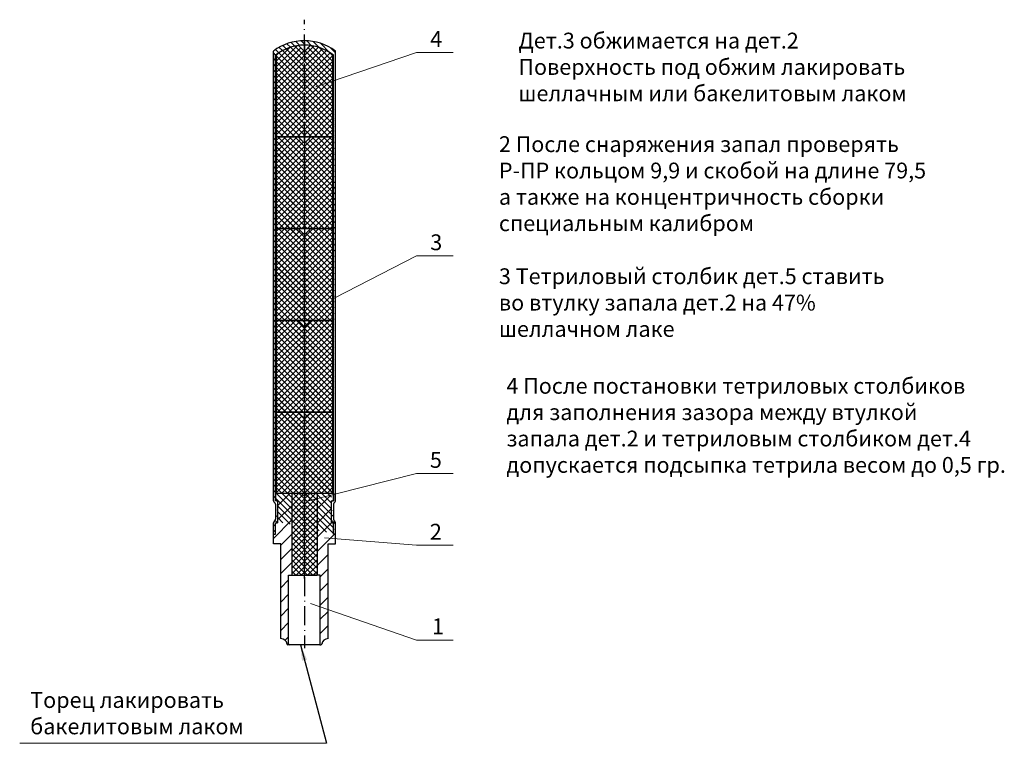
# Model space of a CAD drawing. Units: millimetres. Extents: x -45 to 111, y -40 to 75.
import ezdxf

# ---------------------------------------------------------------- set-up
doc = ezdxf.new("R2010")
doc.units = ezdxf.units.MM
doc.linetypes.add('ACAD_ISO10W100', pattern=[18, 12, -3, 0, -3])
doc.dimstyles.new('ISO-25', dxfattribs={"dimtxt": 2.5, "dimasz": 2.5, "dimexe": 1.25, "dimexo": 0.625, "dimtad": 1, "dimtxsty": 'Standard', "dimcen": 2.5, "dimadec": 0, "dimazin": 0, "dimtfac": 1, "dimtmove": 0, "dimatfit": 3, "dimfxl": 0, "dimarcsym": 0})
pattern_1 = [(45, (0, 0), (-0.4490128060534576, 0.4490128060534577), []), (135, (0, 0), (-0.4490128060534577, -0.4490128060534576), [])]
pattern_2 = [(135, (0, 0), (-0.4490128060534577, -0.4490128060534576), []), (225, (0, 0), (0.4490128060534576, -0.4490128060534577), [])]
pattern_3 = [(45, (0, 0), (-1.122532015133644, 1.122532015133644), [])]

# ---------------------------------------------------------------- blocks, each defined once
blk = doc.blocks.new('tetril_stolbik_8_92')
at = {"lineweight": 15, "ltscale": 0.25}
h = blk.add_hatch(dxfattribs=at)
h.set_pattern_fill('ANSI37', scale=0.2, angle=90, style=0)
h.set_pattern_definition(pattern_2)
h.paths.add_polyline_path([(4.469813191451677e-15, 14.5), (-4.46, 14.5), (-4.46, 5.461744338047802e-16), (-1, 5.461744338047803e-16), (3.367667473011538e-16, 1)])
h.paths.add_polyline_path([(4.460000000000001, 14.5), (4.469813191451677e-15, 14.5), (3.367667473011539e-16, 1), (1, 5.461744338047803e-16), (4.46, 5.461744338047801e-16)])
at = {"color": 1, "linetype": 'ACAD_ISO10W100', "lineweight": 25, "ltscale": 0.25}
blk.add_line((-1.224606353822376e-16, -0.4999999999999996), (7.53132907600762e-15, 24.5), dxfattribs=at)
at = {"color": 7, "lineweight": 30, "ltscale": 0.25}
for p, q in [((-4.46, 5.461744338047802e-16), (-4.459999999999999, 14.5)), ((4.460000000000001, 14.5), (-4.459999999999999, 14.5)), ((4.46, 5.461744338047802e-16), (4.460000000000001, 14.5)), ((-4.46, 5.461744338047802e-16), (4.46, 5.461744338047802e-16)), ((-1, 5.461744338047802e-16), (3.367667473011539e-16, 1)), ((3.367667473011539e-16, 1), (1, 5.461744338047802e-16))]:
    blk.add_line(p, q, dxfattribs=at)
blk = doc.blocks.new('tetril_stolbik_4')
at = {"lineweight": 15, "ltscale": 0.25}
h = blk.add_hatch(dxfattribs=at)
h.set_pattern_fill('ANSI37', scale=0.2, angle=90, style=0)
h.set_pattern_definition(pattern_2)
h.paths.add_polyline_path([(3.857510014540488e-15, 12.5), (-0.4999999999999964, 13), (-1.999999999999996, 13), (-2, 2.449212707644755e-16), (-0.4999999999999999, 2.449212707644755e-16), (1.836909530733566e-16, 0.5000000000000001)])
h.paths.add_polyline_path([(2.000000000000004, 13), (0.5000000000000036, 13), (3.857510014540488e-15, 12.5), (1.836909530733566e-16, 0.5000000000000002), (0.5, 2.449212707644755e-16), (2.000000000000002, 2.449212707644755e-16)])
at = {"color": 1, "linetype": 'ACAD_ISO10W100', "lineweight": 25, "ltscale": 0.25}
blk.add_line((-1.224606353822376e-16, -0.4999999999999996), (7.53132907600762e-15, 24.5), dxfattribs=at)
at = {"color": 7, "lineweight": 30, "ltscale": 0.25}
for p, q in [((-1.999999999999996, 13), (-2, 2.449212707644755e-16)), ((-1.999999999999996, 13), (2.000000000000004, 13)), ((-0.499999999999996, 13), (3.918740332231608e-15, 12.5)), ((3.918740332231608e-15, 12.5), (0.500000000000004, 13)), ((2.000000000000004, 13), (2.000000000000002, 2.449212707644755e-16)), ((-2, 2.449212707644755e-16), (2, 2.449212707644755e-16)), ((1.836909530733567e-16, 0.5000000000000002), (-0.4999999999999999, 2.449212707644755e-16)), ((0.5, 2.449212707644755e-16), (1.836909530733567e-16, 0.5000000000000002))]:
    blk.add_line(p, q, dxfattribs=at)

msp = doc.modelspace()

# ---------------------------------------------------------------- hatches: boundary and pattern name
at = {"linetype": 'ByBlock', "lineweight": 15}
h = msp.add_hatch(dxfattribs=at)
h.set_pattern_fill('ANSI31', scale=0.2, angle=90, style=0)
h.set_pattern_definition([(135, (0, 0), (-0.4490128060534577, -0.4490128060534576), [])])
edge = h.paths.add_edge_path()
edge.add_line((-4.910000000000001, -6.499999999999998), (-4.574999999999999, -6.499999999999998))
edge.add_line((-4.574999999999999, -6.499999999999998), (-4.574999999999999, -4.699999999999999))
edge.add_line((-4.910000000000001, -6.499999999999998), (-4.910000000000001, -4.699999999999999))
edge.add_line((-4.574999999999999, -4.699999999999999), (-4.250000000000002, -4.699999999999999))
edge.add_arc((-4.450000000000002, -4.499999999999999), 0.2000000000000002, 270, 360)
edge.add_arc((-4.574999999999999, -4.699999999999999), 0.3350000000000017, 119.7398696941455, 180)
edge.add_arc((-4.890000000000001, -4.148638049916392), 0.3, 299.7398696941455, 360)
edge.add_line((-4.25, -1.200000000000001), (-4.250000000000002, -4.699999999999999))
edge.add_line((-4.59, -1.751361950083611), (-4.590000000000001, -4.148638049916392))
edge.add_arc((-4.45, -1.4), 0.2000000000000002, 359.9999999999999, 449.9999999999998)
edge.add_line((-4.25, -1.200000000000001), (-4.575, -1.2))
edge.add_line((-4.574999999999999, -1.2), (-4.574999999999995, 69.24301060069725))
edge.add_arc((-4.89, -1.751361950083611), 0.3, 0, 60.26013030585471)
edge.add_arc((-4.574999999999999, -1.2), 0.3350000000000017, 180, 240.2601303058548)
edge.add_line((-4.910000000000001, -1.2), (-4.909999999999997, 69.8674881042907))
edge.add_arc((3.385697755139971e-15, 63.29999999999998), 8.200000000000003, 53.21739364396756, 126.7826063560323)
edge.add_arc((3.385697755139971e-15, 63.29999999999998), 7.5, 52.41049703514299, 127.5895029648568)
edge.add_line((4.574999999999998, -1.200000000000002), (4.575000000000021, 69.24301060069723))
edge.add_line((4.91, -1.200000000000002), (4.910000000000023, 69.86748810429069))
edge.add_line((4.25, -1.200000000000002), (4.575, -1.200000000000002))
edge.add_arc((4.450000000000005, -1.400000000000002), 0.2000000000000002, 90.00000000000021, 180)
edge.add_arc((4.575000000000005, -1.200000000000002), 0.3350000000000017, 299.7398696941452, 360)
edge.add_arc((4.890000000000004, -1.751361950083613), 0.3, 119.7398696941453, 180)
edge.add_line((4.25, -1.200000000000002), (4.249999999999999, -4.700000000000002))
edge.add_line((4.590000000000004, -1.751361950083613), (4.590000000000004, -4.148638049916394))
edge.add_arc((4.450000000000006, -4.500000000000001), 0.2000000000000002, 180, 270)
edge.add_line((4.574999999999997, -4.700000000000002), (4.249999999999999, -4.700000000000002))
edge.add_arc((4.890000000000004, -4.148638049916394), 0.3, 180, 240.2601303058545)
edge.add_arc((4.575000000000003, -4.700000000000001), 0.3350000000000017, 0, 60.26013030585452)
edge.add_line((4.574999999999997, -6.5), (4.574999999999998, -4.700000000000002))
edge.add_line((4.909999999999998, -6.5), (4.909999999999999, -4.696309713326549))
edge.add_line((4.574999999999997, -6.500000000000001), (4.909999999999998, -6.5))
h = msp.add_hatch(dxfattribs=at)
h.set_pattern_fill('ANSI37', scale=0.2, style=0)
h.set_pattern_definition(pattern_1)
h.paths.add_polyline_path([(3.093486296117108e-15, 69.79999999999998), (-0.9407636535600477, 70.74076365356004, 0.1284710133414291), (-4.459999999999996, 69.32979269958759), (-4.459999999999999, 56.29999999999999), (-2.692778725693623e-15, 56.29999999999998)])
h.paths.add_polyline_path([(4.460000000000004, 69.32979269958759, 0.1284710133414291), (0.940763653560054, 70.74076365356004), (0.9287125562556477, 70.72871255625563), (3.093486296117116e-15, 69.8), (-2.692778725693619e-15, 56.29999999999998), (4.460000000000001, 56.29999999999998)])
h = msp.add_hatch(dxfattribs=at)
h.set_pattern_fill('ANSI37', scale=0.2, style=0)
h.set_pattern_definition(pattern_1)
h.paths.add_polyline_path([(-1.733224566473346e-14, 11.79999999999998), (-1.000000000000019, 12.79999999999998), (-4.460000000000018, 12.79999999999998), (-4.460000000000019, 1.77635683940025e-15), (3.061515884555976e-17, 1.77635683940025e-15), (1.224606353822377e-16, 0.5)])
h.paths.add_polyline_path([(4.459999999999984, 12.79999999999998), (0.9999999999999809, 12.79999999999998), (-1.733224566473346e-14, 11.79999999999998), (-2.118975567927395e-14, 2.799999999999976), (1.224606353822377e-16, 0.5), (3.061515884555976e-17, 1.77635683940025e-15), (4.45999999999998, 1.77635683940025e-15)])
h = msp.add_hatch(dxfattribs=at)
h.set_pattern_fill('ANSI31', scale=0.5, style=0)
h.set_pattern_definition(pattern_3)
h.paths.add_polyline_path([(4.25, -1.200000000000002), (4.574999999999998, -1.200000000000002), (4.574999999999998, -0.2095700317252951), (2.000000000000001, -0.8576162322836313), (2, -13), (2.499999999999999, -13), (2.499999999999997, -17.98914532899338), (3.749999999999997, -18.42037202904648), (3.75, -8), (4.909999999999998, -8), (4.909999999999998, -6.5), (4.574999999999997, -6.500000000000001), (4.574999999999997, -4.700000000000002), (4.249999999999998, -4.700000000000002)])
h.paths.add_polyline_path([(-1.999999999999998, 1.77635683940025e-15), (-4.460000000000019, 1.77635683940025e-15), (-4.574999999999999, 5.602574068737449e-16), (-4.574999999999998, -1.2), (-4.25, -1.200000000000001), (-4.250000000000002, -4.699999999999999), (-4.574999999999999, -4.699999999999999), (-4.575, -6.499999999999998), (-4.910000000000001, -6.499999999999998), (-4.910000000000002, -7.999999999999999), (-3.750000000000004, -7.999999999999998), (-3.750000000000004, -23, -0.3819534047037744), (-2.756196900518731, -23.88884515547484, 0.3394113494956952), (-2.611314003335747, -24), (-2.500000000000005, -24), (-2.350000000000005, -24, -0.4142135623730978), (-2.500000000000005, -23.85), (-2.500000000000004, -13), (-2.000000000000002, -13)])
h = msp.add_hatch(dxfattribs=at)
h.set_pattern_fill('ANSI31', scale=0.5, style=0)
h.set_pattern_definition(pattern_3)
h.paths.add_polyline_path([(3.749999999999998, -18.42037202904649), (2.499999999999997, -17.98914532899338), (2.499999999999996, -23.85, -0.4142135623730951), (2.349999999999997, -24), (2.499999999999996, -24), (2.611314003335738, -24, 0.3394113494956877), (2.756196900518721, -23.88884515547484, -0.3819534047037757), (3.749999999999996, -23)])

# ---------------------------------------------------------------- linework, layer by layer
at = {"color": 1, "linetype": 'ACAD_ISO10W100', "lineweight": 25, "ltscale": 0.25}
for p, q in [((1.224606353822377e-16, 0.5), (4.673465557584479e-15, 74.82600538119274)), ((3.736404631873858e-15, 71.29999999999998), (-6.978900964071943e-15, 46.29999999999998)), ((1.224606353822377e-16, 0.5), (-4.469813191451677e-15, -24.5)), ((1.224606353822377e-16, 0.5), (-4.469813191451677e-15, -24.5))]:
    msp.add_line(p, q, dxfattribs=at)
at = {"color": 7, "lineweight": 30, "ltscale": 0.25}
for p, q in [((3.093486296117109e-15, 69.79999999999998), (-0.9407636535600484, 70.74076365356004)), ((0.9003744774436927, 70.70037447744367), (3.093486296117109e-15, 69.79999999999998)), ((0.9376624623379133, 70.7376624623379), (0.9287125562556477, 70.72871255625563)), ((-4.459999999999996, 69.32979269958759), (-4.459999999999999, 56.29999999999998)), ((4.460000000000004, 69.32979269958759), (4.460000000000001, 56.29999999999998)), ((-4.459999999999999, 56.29999999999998), (4.460000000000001, 56.29999999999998)), ((4.459999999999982, 12.79999999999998), (-4.460000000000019, 12.79999999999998)), ((-4.460000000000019, 12.79999999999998), (-4.460000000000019, 1.77635683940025e-15)), ((-1.77635683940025e-14, 11.79999999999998), (-1.000000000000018, 12.79999999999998)), ((0.9999999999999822, 12.79999999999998), (-1.77635683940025e-14, 11.79999999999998)), ((4.459999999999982, 12.79999999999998), (4.45999999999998, 1.77635683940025e-15))]:
    msp.add_line(p, q, dxfattribs=at)
at = {"color": 7, "linetype": 'ByBlock', "lineweight": 15}
for p, q in [((3.093486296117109e-15, 69.79999999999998), (0.9287125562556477, 70.72871255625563)), ((17.7347467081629, 69.62612580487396), (1.796051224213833, 64.20883126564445)), ((23.53265235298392, 69.62612580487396), (17.7347467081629, 69.62612580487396)), ((17.73474670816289, 37.48726621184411), (4.715910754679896, 30.78908844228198)), ((23.53265235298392, 37.48726621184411), (17.73474670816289, 37.48726621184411)), ((17.73474670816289, 3.102322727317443), (0.4154741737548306, -1.256391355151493)), ((23.53265235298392, 3.102322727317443), (17.73474670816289, 3.102322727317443)), ((-4.460000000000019, 1.77635683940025e-15), (4.45999999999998, 1.77635683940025e-15)), ((17.73474670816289, -8.242249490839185), (3.188885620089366, -7.070729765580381)), ((23.53265235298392, -8.242249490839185), (17.73474670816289, -8.242249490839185)), ((17.73474670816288, -23.24484896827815), (0.9506714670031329, -17.4546558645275)), ((17.73474670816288, -23.24484896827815), (23.53265235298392, -23.24484896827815)), ((3.494205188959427, -39.54998238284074), (-0.6333276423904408, -24)), ((-45.03545495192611, -39.54998238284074), (3.494205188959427, -39.54998238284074))]:
    msp.add_line(p, q, dxfattribs=at)
at = {"color": 7, "linetype": 'ByBlock', "lineweight": 30}
for p, q in [((-4.910000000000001, -1.2), (-4.909999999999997, 69.8674881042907)), ((-4.574999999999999, -1.2), (-4.574999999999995, 69.24301060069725)), ((4.574999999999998, -1.200000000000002), (4.575000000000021, 69.24301060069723)), ((4.91, -1.200000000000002), (4.910000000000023, 69.86748810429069)), ((-4.575, 5.602574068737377e-16), (4.575, -1.680772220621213e-15)), ((-4.575, 0), (-4.575, -1.2)), ((-4.575, 0), (-4.575, -1.2)), ((-4.25, -1.200000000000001), (-4.575, -1.2)), ((-4.25, -1.200000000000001), (-4.250000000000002, -4.699999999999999)), ((-2, -3.153361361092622e-16), (-2.000000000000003, -13)), ((2, -1.050099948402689e-15), (1.999999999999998, -13)), ((4.25, -1.200000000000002), (4.575, -1.200000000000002)), ((4.25, -1.200000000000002), (4.249999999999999, -4.700000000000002)), ((4.575, -1.680772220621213e-15), (4.575, -1.200000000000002)), ((4.575, -1.680772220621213e-15), (4.575, -1.200000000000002)), ((-4.59, -1.751361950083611), (-4.590000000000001, -4.148638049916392)), ((4.590000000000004, -1.751361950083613), (4.590000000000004, -4.148638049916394)), ((-4.910000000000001, -6.499999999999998), (-4.910000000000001, -4.699999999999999)), ((-4.574999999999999, -4.699999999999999), (-4.250000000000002, -4.699999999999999)), ((-4.574999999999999, -6.499999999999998), (-4.574999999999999, -4.699999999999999)), ((-4.574999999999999, -6.499999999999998), (-4.574999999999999, -4.699999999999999)), ((-4.574999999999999, -6.499999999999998), (-4.574999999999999, -4.699999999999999)), ((4.574999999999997, -4.700000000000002), (4.249999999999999, -4.700000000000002)), ((4.574999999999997, -6.500000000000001), (4.574999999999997, -4.700000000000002)), ((4.574999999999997, -6.500000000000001), (4.574999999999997, -4.700000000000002)), ((4.574999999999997, -6.5), (4.574999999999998, -4.700000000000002)), ((4.909999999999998, -6.5), (4.909999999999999, -4.696309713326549)), ((-4.910000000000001, -7.999999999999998), (-4.910000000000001, -6.499999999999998)), ((-4.910000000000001, -6.499999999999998), (-4.574999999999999, -6.499999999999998)), ((-4.910000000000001, -6.499999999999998), (-4.574999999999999, -6.499999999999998)), ((4.909999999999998, -6.500000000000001), (4.574999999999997, -6.500000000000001)), ((4.909999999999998, -6.500000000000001), (4.574999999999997, -6.500000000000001)), ((4.909999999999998, -8), (4.909999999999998, -6.500000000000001)), ((-3.750000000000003, -7.999999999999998), (-4.910000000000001, -7.999999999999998)), ((-3.750000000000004, -23), (-3.750000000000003, -7.999999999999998)), ((3.749999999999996, -23), (3.75, -8)), ((3.75, -8), (4.909999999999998, -8)), ((-2.500000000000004, -13), (-2.357367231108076e-15, -13)), ((-2.500000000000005, -23.85), (-2.500000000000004, -13)), ((2.499999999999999, -13), (-2.357367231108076e-15, -13)), ((2.499999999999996, -23.85), (2.499999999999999, -13)), ((-2.500000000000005, -24), (-2.611314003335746, -24)), ((2.499999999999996, -24), (-2.500000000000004, -24)), ((2.499999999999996, -24), (2.611314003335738, -24))]:
    msp.add_line(p, q, dxfattribs=at)
at = {"color": 7, "lineweight": 15, "ltscale": 0.25}
for p, q in [((-4.910000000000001, -6.499999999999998), (-4.574999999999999, -6.499999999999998)), ((4.574999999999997, -6.500000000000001), (4.909999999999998, -6.5))]:
    msp.add_line(p, q, dxfattribs=at)
at = {"color": 7, "linetype": 'ByBlock', "lineweight": 30}
for centre, radius, start, end in [((3.385697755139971e-15, 63.29999999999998), 8.200000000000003, 53.21739364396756, 126.7826063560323), ((3.385697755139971e-15, 63.29999999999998), 7.5, 52.41049703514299, 127.5895029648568), ((-4.574999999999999, -1.2), 0.3350000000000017, 180, 240.2601303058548), ((-4.89, -1.751361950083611), 0.3, 0, 60.26013030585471), ((-4.45, -1.4), 0.2000000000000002, 359.9999999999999, 89.99999999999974), ((4.450000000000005, -1.400000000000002), 0.2000000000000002, 90.00000000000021, 180), ((4.890000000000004, -1.751361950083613), 0.3, 119.7398696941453, 180), ((4.575000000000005, -1.200000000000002), 0.3350000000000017, 299.7398696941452, 0), ((-4.574999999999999, -4.699999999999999), 0.3350000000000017, 119.7398696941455, 180), ((-4.890000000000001, -4.148638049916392), 0.3, 299.7398696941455, 0), ((-4.450000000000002, -4.499999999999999), 0.2000000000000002, 270, 0), ((4.450000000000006, -4.500000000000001), 0.2000000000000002, 180, 270), ((4.890000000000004, -4.148638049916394), 0.3, 180, 240.2601303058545), ((4.575000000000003, -4.700000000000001), 0.3350000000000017, 0, 60.26013030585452), ((-3.750000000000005, -24), 1, 6.381891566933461, 90), ((3.749999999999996, -24), 1, 90, 173.6181084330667), ((-2.611314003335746, -23.85), 0.1499999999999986, 180, 270), ((-2.350000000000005, -23.85), 0.1499999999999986, 180, 270), ((2.349999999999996, -23.85), 0.1499999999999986, 270, 1.836185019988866e-27), ((2.611314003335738, -23.85), 0.1499999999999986, 270, 1.836185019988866e-27)]:
    msp.add_arc(centre, radius, start, end, dxfattribs=at)

# ---------------------------------------------------------------- block references
at = {"color": 7, "linetype": 'ByBlock', "lineweight": 15, "rotation": 180}
for p in [(3.552713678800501e-15, 56.29999999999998), (-3.552713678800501e-15, 41.79999999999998), (-1.06581410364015e-14, 27.29999999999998)]:
    msp.add_blockref('tetril_stolbik_8_92', p, dxfattribs=at)
at = {"color": 7, "linetype": 'ByBlock', "lineweight": 15}
msp.add_blockref('tetril_stolbik_4', (-2.357367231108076e-15, -13), dxfattribs=at)

# ---------------------------------------------------------------- texts
for s, p in [('4', (19.89752792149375, 70.52962284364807)), ('Дет.3 обжимается на дет.2', (33.8388314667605, 70.27402758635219)), ('Поверхность под обжим лакировать', (33.8388314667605, 66.10736091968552)), ('шеллачным или бакелитовым лаком', (33.8388314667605, 61.94069425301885)), ('2 После снаряжения запал проверять', (30.75217887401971, 53.90329321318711)), ('Р-ПР кольцом 9,9 и скобой на длине 79,5', (30.75217887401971, 49.73662654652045)), ('а также на концентричность сборки', (30.75217887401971, 45.56995987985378)), ('специальным калибром', (30.75217887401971, 41.40329321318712)), ('3', (19.89752792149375, 38.39076325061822)), ('3 Тетриловый столбик дет.5 ставить', (30.75217887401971, 33.02467572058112)), ('во втулку запала дет.2 на 47%', (30.75217887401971, 28.85800905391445)), ('шеллачном лаке', (30.75217887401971, 24.69134238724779)), ('4 После постановки тетриловых столбиков', (31.93935260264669, 15.70491344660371)), ('для заполнения зазора между втулкой ', (31.93935260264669, 11.53824677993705)), ('запала дет.2 и тетриловым столбиком дет.4', (31.93935260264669, 7.37158011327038)), ('5', (19.8355170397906, 3.990322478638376)), ('допускается подсыпка тетрила весом до 0,5 гр.', (31.93935260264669, 3.204913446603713)), ('2', (19.8355170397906, -7.354249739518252)), ('1', (20.16807279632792, -22.30451037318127)), ('Торец лакировать', (-43.37131732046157, -33.95813928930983)), ('бакелитовым лаком', (-43.37131732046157, -38.12480595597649))]:
    msp.add_text(s, height=2.5, dxfattribs=at).set_placement(p)

# ---------------------------------------------------------------- leaders
msp.add_leader([(-0.6333276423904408, -24), (3.494205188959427, -39.54998238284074)], dimstyle='ISO-25', override={"dimgap": 0.625, "dimtad": 0}, dxfattribs=at)

doc.saveas('drawing.dxf')
